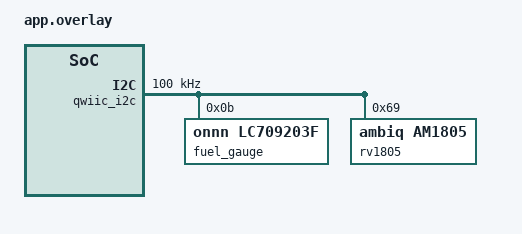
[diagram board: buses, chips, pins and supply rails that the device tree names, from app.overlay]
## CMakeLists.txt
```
# SPDX-License-Identifier: Apache-2.0
#
# ArtemisNano_Hive_Multisense firmware. Adding the app directory to BOARD_ROOT
# makes boards/sparkfun/artemis_nano available as -b sparkfun_artemis_nano.

cmake_minimum_required(VERSION 3.20.0)
list(APPEND BOARD_ROOT ${CMAKE_CURRENT_SOURCE_DIR})
find_package(Zephyr REQUIRED HINTS $ENV{ZEPHYR_BASE})
project(artemis_multisense)

target_sources(app PRIVATE src/main.c src/rv1805.c src/opt4048.c src/bno085.c
  src/person_sensor.c src/hive_ble.c)

# CEVA SH-2 sensor hub library (vendored, unmodified; see lib/sh2/VENDORED.txt).
target_sources(app PRIVATE
  lib/sh2/sh2.c
  lib/sh2/sh2_SensorValue.c
  lib/sh2/sh2_util.c
  lib/sh2/shtp.c
)
target_include_directories(app PRIVATE lib/sh2)
```

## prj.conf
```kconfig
# M4: sensors (RV-1805, LC709203F, OPT4048, BNO085) + BLE MagNET advert and HCP GATT.
CONFIG_GPIO=y
CONFIG_PRINTK=y
CONFIG_I2C=y
CONFIG_RTC=y
CONFIG_FUEL_GAUGE=y
CONFIG_LOG=y
CONFIG_LOG_MODE_IMMEDIATE=y
CONFIG_FPU=y
CONFIG_CBPRINTF_FP_SUPPORT=y
CONFIG_MAIN_STACK_SIZE=2048

# BLE peripheral: MagNET advert + Hanasu HCP GATT service
CONFIG_BT=y
CONFIG_BT_PERIPHERAL=y
CONFIG_BT_MAX_CONN=1
CONFIG_BT_DEVICE_NAME_DYNAMIC=y
CONFIG_BT_DEVICE_NAME_MAX=16
CONFIG_BT_DEVICE_NAME="MagNET"
CONFIG_BT_GATT_DYNAMIC_DB=n
CONFIG_BT_ATT_PREPARE_COUNT=4

# Pairing: Just Works, HCP-AUTH read forces encryption; bonds kept in flash
CONFIG_BT_SMP=y
CONFIG_BT_SMP_ALLOW_UNAUTH_OVERWRITE=y
CONFIG_BT_SETTINGS=y
CONFIG_SETTINGS=y
CONFIG_FLASH=y
CONFIG_FLASH_MAP=y
CONFIG_NVS=y
```

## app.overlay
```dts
/*
 * ArtemisNano_Hive_Multisense app overlay.
 * Qwiic bus (IOM2, SCL pad 27 / SDA pad 25) at 100 kHz with the Multisensor chain:
 *   0x0B LC709203F fuel gauge   (M2, in-tree driver)
 *   0x44 OPT4048 color          (M3, out-of-tree driver)
 *   0x4A BNO085 IMU             (M3, CEVA SH-2 port)
 *   0x69 RV-1805 RTC            (M2, in-tree ambiq,am1805 driver; RV-1805 = AM1805)
 */

/ {
	aliases {
		rtc = &rv1805;
		fuel-gauge0 = &fuel_gauge;
	};
};

&qwiic_i2c {
	clock-frequency = <I2C_BITRATE_STANDARD>;
	status = "okay";

	fuel_gauge: lc709203f@b {
		compatible = "onnn,lc709203f";
		reg = <0x0b>;
		apa = "2000mAh";		/* 3.7 V 2000 mAh LiPo */
		battery-profile = <0x01>;	/* 4.2 V charged (Adafruit default) */
	};

	/* Alarm (CONFIG_RTC_ALARM) needs am1805-gpios = RV-1805 INT -> D6 (pad 43); not wired yet. */
	rv1805: rv1805@69 {
		compatible = "ambiq,am1805";
		reg = <0x69>;
	};
};
```

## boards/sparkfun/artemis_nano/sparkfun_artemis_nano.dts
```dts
/*
 * SPDX-License-Identifier: Apache-2.0
 *
 * SparkFun RedBoard Artemis Nano (DEV-15443), Artemis module = Ambiq Apollo3 Blue.
 * Derived from boards/ambiq/apollo3_evb (Zephyr v4.4.2).
 */

/dts-v1/;
#include <ambiq/ambiq_apollo3_blue.dtsi>

#include "sparkfun_artemis_nano-pinctrl.dtsi"

/ {
	model = "SparkFun RedBoard Artemis Nano";
	compatible = "sparkfun,artemis-nano";

	chosen {
		zephyr,itcm = &tcm;
		zephyr,sram = &sram0;
		zephyr,flash = &flash0;
		zephyr,console = &uart0;
		zephyr,shell-uart = &uart0;
		zephyr,flash-controller = &flash;
		zephyr,code-partition = &slot0_partition;
		zephyr,bt-hci = &bt_hci_apollo;
	};

	aliases {
		watchdog0 = &wdt0;
		led0 = &led0;
	};

	leds {
		compatible = "gpio-leds";

		/* Blue LED D1 on pad 19 via 1k to GND: active high */
		led0: led_0 {
			gpios = <&gpio0_31 19 GPIO_ACTIVE_HIGH>;
			label = "Blue LED";
		};
	};
};

&flash0 {
	erase-block-size = <8192>;
	write-block-size = <4>;

	partitions {
		compatible = "fixed-partitions";
		#address-cells = <1>;
		#size-cells = <1>;

		/* Ambiq secure bootloader: never write */
		internal_boot_partition: partition@0 {
			label = "internal_bootloader";
			reg = <0x00000000 0xc000>;
			read-only;
		};

		/* SparkFun Variable Loader (SVL): USB recovery path, never write */
		svl_partition: partition@c000 {
			label = "svl";
			reg = <0x0000c000 0x4000>;
			read-only;
		};

		/* Application, linked here via CONFIG_FLASH_LOAD_OFFSET=0x10000 */
		slot0_partition: partition@10000 {
			label = "image-0";
			reg = <0x00010000 0xec000>;
		};

		/* 16 KB at the end of the 1 MB flash */
		storage_partition: partition@fc000 {
			label = "storage";
			reg = <0x000fc000 0x4000>;
		};
	};
};

&stimer0 {
	clk-source = <3>;
};

&uart0 {
	current-speed = <115200>;
	pinctrl-0 = <&uart0_default>;
	pinctrl-names = "default";
	status = "okay";
};

&wdt0 {
	status = "okay";
};

/* Qwiic connector, off until a phase needs it */
&iom2 {
	qwiic_i2c: i2c {
		pinctrl-0 = <&i2c2_default>;
		pinctrl-names = "default";
		clock-frequency = <I2C_BITRATE_STANDARD>;
		scl-gpios = <&gpio0_31 27 (GPIO_OPEN_DRAIN | GPIO_PULL_UP)>;
		sda-gpios = <&gpio0_31 25 (GPIO_OPEN_DRAIN | GPIO_PULL_UP)>;
		status = "disabled";
	};
};

/*
 * Servo PWM on D9 (pad 39), timer 2 segment B. Off for phase 2; phase 3 enables it
 * and moves timer 2 to the 3 MHz clock so a 20 ms frame (60000 counts) fits in 16 bits.
 */
&timer2 {
	pwm2: pwm {
		timer-segment = "SEGMENT_B";
		pwm-type = "PWM_REPEAT";
		pinctrl-0 = <&pwm2_default>;
		pinctrl-names = "default";
		status = "disabled";
	};
};

/*
 * BLE: the Apollo3 Blue radio sits inside the Artemis module behind the internal
 * BLEIF, so no pads are needed. The EVB's bleif_default pinmux (pads 30-33, 35, 41)
 * is only applied with CONFIG_SPI_AMBIQ_BLEIF_TIMING_TRACE, so it is left out here
 * and header pins A1/A5/A14/A15 stay free.
 */
&bleif {
	status = "okay";
};

&gpio0_31 {
	status = "okay";
};

&gpio32_63 {
	status = "okay";
};
```

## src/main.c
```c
/*
 * SPDX-License-Identifier: Apache-2.0
 *
 * ArtemisNano_Hive_Multisense.
 *
 * M4: sensors (M2/M3) + BLE.
 *   - RV-1805 RTC (ambiq,am1805 driver + trickle charger), LC709203F fuel gauge,
 *     OPT4048 color (src/opt4048.c), BNO085 IMU via CEVA SH-2 (src/bno085.c).
 *   - Every 10 s: sample everything into one snapshot, print it, refresh the advert.
 *   - BLE (src/hive_ble.c): MagNET advert with the sensor bitmap + readings, and
 *     the Hanasu HCP GATT service answering WHOAMI/STATUS/CAPS/SENSE.
 *
 * Boot check (from P2): blue LED lights before the kernel starts.
 *   LED on, no text -> console pins/baud wrong.  LED off -> image never ran.
 *
 * Blue LED, once running:
 *   1 Hz even blink      -> up, advertising, nobody connected
 *   short pulse / 2.5 s  -> a central is connected
 *   solid on             -> never reached main() (see the boot check above)
 */

#include <stdio.h>
#include <string.h>
#include <zephyr/kernel.h>
#include <zephyr/init.h>
#include <zephyr/sys/byteorder.h>
#include <zephyr/sys/printk.h>
#include <zephyr/drivers/gpio.h>
#include <zephyr/drivers/i2c.h>
#include <zephyr/drivers/rtc.h>
#include <zephyr/drivers/fuel_gauge.h>
#include <cmsis_core.h>
#include <am_mcu_apollo.h>
#include "rv1805.h"
#include "opt4048.h"
#include "bno085.h"
#include "person_sensor.h"
#include "multisense.h"
#include "hive_ble.h"

#define BLUE_LED_PAD 19
#define RV1805_ADDR  0x69
#define OPT4048_ADDR 0x44
#define BNO085_ADDR  0x4A
#define PERSON_ADDR  PERSON_SENSOR_ADDR

/*
 * Full-bus sweep at boot, in addition to the targeted probe of known[].
 *
 * Off by default: it puts a 1-byte read on every one of the ~112 valid 7-bit
 * addresses, including ones no driver owns, and a working node does not need
 * that traffic on every boot. Turn it on when a part that should be present is
 * missing — it is the only way to see a device that moved address (an OPT4048
 * strapped to 0x45 instead of 0x44, say) or one that nobody has added to
 * known[] yet. known[] alone answers "is the Person Sensor there", so the sweep
 * is for the addresses we have not thought of.
 */
#define MS_BUS_SWEEP 0

#define REPORT_PERIOD_MS 10000

/*
 * Blue LED cadence — the only thing this board can say without a console, so
 * the two states must not look alike from across the bench:
 *   advertising, nobody connected : 1 Hz even blink (as it has always been)
 *   a central connected           : a short pulse every 2.5 s
 * The connected pattern is also the cheaper one (80 ms on in 2500 ms, ~3% duty
 * against 50%), which matters for M5: the red power LED is ~1.5 mA and this one
 * is on the same order.
 */
#define LED_ADV_ON_MS    500
#define LED_ADV_OFF_MS   500
#define LED_CONN_ON_MS    80
#define LED_CONN_OFF_MS 2420

/*
 * Last OPT4048 read, kept for the console only (not part of ms_readings, which
 * crosses to hive_ble). M3 printed the error code and the raw channel codes;
 * M4 dropped both, which is why a node whose light sensor stopped reporting
 * could only say "no data" -- no errno, no way to tell darkness from a fault.
 */
static int light_err;
static int presence_err;
static uint32_t light_raw[4];
static uint8_t light_counter;

static const struct gpio_dt_spec led = GPIO_DT_SPEC_GET(DT_ALIAS(led0), gpios);
static const struct device *const qwiic = DEVICE_DT_GET(DT_NODELABEL(qwiic_i2c));
static const struct device *const rtc = DEVICE_DT_GET(DT_ALIAS(rtc));
static const struct device *const gauge = DEVICE_DT_GET(DT_ALIAS(fuel_gauge0));

static const struct {
	uint8_t addr;
	const char *name;
	uint16_t caps;
} known[] = {
	{0x0B, "LC709203F fuel gauge", MS_CAP_BATTERY},
	{0x44, "OPT4048 color", MS_CAP_LUX | MS_CAP_COLOR},
	{0x45, "OPT4048 color (alt)", 0},
	{0x46, "OPT4048 color (alt)", 0},
	{0x4A, "BNO085 IMU", MS_CAP_ORIENTATION},
	{0x4B, "BNO085 IMU (alt)", 0},
	/*
	 * Useful Sensors Person Sensor. v1.0, v1.1 and v2.0 all answer here and are
	 * software-compatible. The M1 scan (2026-10-19) saw an ACK at 0x62 and
	 * recorded it as an unexpected address from a faulty AK9753 board; 0x62 is
	 * this part's documented address, so it was most likely answering correctly.
	 *
	 * src/person_sensor.c reads it, so the capability is claimed here and
	 * cleared again by sensors_bringup() if the probe does not answer.
	 */
	{0x62, "Person Sensor (Useful Sensors)", MS_CAP_PRESENCE},
	{0x69, "RV-1805 RTC", MS_CAP_TIME},
};

static K_MUTEX_DEFINE(snap_lock);
static struct ms_readings snap = {.soc_pct = 0xFF, .tbat_dc = TBAT_NONE_DC};
static uint16_t probed_caps;
static uint8_t device_id[4];

/* Runs before the kernel, drivers and console: drive the LED pad with the HAL. */
static int early_led_on(void)
{
	am_hal_gpio_pinconfig(BLUE_LED_PAD, g_AM_HAL_GPIO_OUTPUT);
	am_hal_gpio_output_set(BLUE_LED_PAD);
	return 0;
}
SYS_INIT(early_led_on, PRE_KERNEL_1, 0);

void ms_readings_get(struct ms_readings *out)
{
	k_mutex_lock(&snap_lock, K_FOREVER);
	*out = snap;
	k_mutex_unlock(&snap_lock);
}

const uint8_t *ms_device_id(void)
{
	return device_id;
}

/* FNV-1a over the two 32-bit chip ID words: stable per part, spreads low-bit differences. */
static void device_id_init(void)
{
	am_hal_mcuctrl_device_t dev;
	uint32_t h = 2166136261u;

	am_hal_mcuctrl_info_get(AM_HAL_MCUCTRL_INFO_DEVICEID, &dev);
	uint32_t words[2] = {dev.ui32ChipID0, dev.ui32ChipID1};

	for (int w = 0; w < 2; w++) {
		for (int b = 0; b < 4; b++) {
			h ^= (words[w] >> (8 * b)) & 0xFF;
			h *= 16777619u;
		}
	}
	sys_put_be32(h, device_id);
	printk("chip id %08x %08x -> node id %02x%02x%02x%02x\n", dev.ui32ChipID0,
	       dev.ui32ChipID1, device_id[0], device_id[1], device_id[2], device_id[3]);
}

/*
 * Probe only the known Multisensor addresses: the I2C driver logs every NACK as an
 * error, so a full 0x08-0x77 sweep floods the console. Answers set the advert's
 * sensor bitmap; a driver that then fails to start clears its bit again.
 */
#if MS_BUS_SWEEP
/* 0x00-0x07 and 0x78-0x7F are reserved by the I2C spec, so they are skipped. */
static void qwiic_sweep(void)
{
	int found = 0;

	printk("qwiic sweep (0x08-0x77):");
	for (uint8_t addr = 0x08; addr <= 0x77; addr++) {
		uint8_t b;

		if (i2c_read(qwiic, &b, 1, addr) != 0) {
			continue;
		}

		const char *name = "not in known[]";

		for (size_t i = 0; i < ARRAY_SIZE(known); i++) {
			if (known[i].addr == addr) {
				name = known[i].name;
				break;
			}
		}
		printk("\n  0x%02x  %s", addr, name);
		found++;
	}
	printk(found ? "\n  %d device(s)\n" : " nothing\n", found);
}
#endif /* MS_BUS_SWEEP */

static void qwiic_scan(void)
{
	int found = 0;

	printk("qwiic probe:");
	for (size_t i = 0; i < ARRAY_SIZE(known); i++) {
		uint8_t b;

		/* A 1-byte read is the probe; all four parts tolerate it. */
		if (i2c_read(qwiic, &b, 1, known[i].addr) == 0) {
			printk("\n  0x%02x  %s", known[i].addr, known[i].name);
			probed_caps |= known[i].caps;
			found++;
		}
	}
	printk(found ? "\n  %d device(s)\n" : " no devices\n", found);
}

/* Build timestamp -> rtc_time, used once when the RTC holds no valid time. */
static void build_time(struct rtc_time *t)
{
	static const char months[] = "JanFebMarAprMayJunJulAugSepOctNovDec";
	char mon[4] = {0};
	int day = 1, year = 2026, h = 0, m = 0, s = 0;
	const char *p;

	sscanf(__DATE__, "%3s %d %d", mon, &day, &year);
	sscanf(__TIME__, "%d:%d:%d", &h, &m, &s);
	p = strstr(months, mon);

	memset(t, 0, sizeof(*t));
	t->tm_year = year - 1900;
	t->tm_mon = p ? (int)((p - months) / 3) : 0;
	t->tm_mday = day;
	t->tm_hour = h;
	t->tm_min = m;
	t->tm_sec = s;
	t->tm_wday = -1;
	t->tm_yday = -1;
	t->tm_isdst = -1;
}

static void rtc_bringup(void)
{
	struct rtc_time now;
	int err;

	err = rv1805_board_init(qwiic, RV1805_ADDR);
	if (err) {
		printk("rv1805: board init failed (%d)\n", err);
	}
	if (!device_is_ready(rtc)) {
		printk("rtc: driver not ready\n");
		probed_caps &= ~MS_CAP_TIME;
		return;
	}

	err = rtc_get_time(rtc, &now);
	if (err || now.tm_year + 1900 < 2026) {
		struct rtc_time t;

		build_time(&t);
		printk("rtc: no valid time (err %d, year %d); setting build time\n", err,
		       err ? 0 : now.tm_year + 1900);
		err = rtc_set_time(rtc, &t);
		if (err) {
			printk("rtc: set failed (%d)\n", err);
		}
	} else {
		printk("rtc: kept time across reset\n");
	}
}

static void sensors_bringup(void)
{
	int err = opt4048_init(qwiic, OPT4048_ADDR);

	if (err) {
		printk("opt4048: init failed (%d)\n", err);
		probed_caps &= ~(MS_CAP_LUX | MS_CAP_COLOR);
	}

	err = bno085_start(qwiic, BNO085_ADDR);
	if (err) {
		printk("bno085: start failed (%d)\n", err);
		probed_caps &= ~MS_CAP_ORIENTATION;
	}
	if (probed_caps & MS_CAP_PRESENCE) {
		err = person_sensor_init(qwiic, PERSON_ADDR);
		if (err) {
			printk("person: init failed (%d)\n", err);
			probed_caps &= ~MS_CAP_PRESENCE;
		}
	}
	if (!device_is_ready(gauge)) {
		probed_caps &= ~MS_CAP_BATTERY;
	}
}

/* Always TBAT_NONE_DC until a thermistor is fitted (then: FUEL_GAUGE_TEMPERATURE
 * with TSENSE enabled in the driver).
 */
static int16_t battery_temp_dc(void)
{
	return TBAT_NONE_DC;
}

/* Read every sensor into a fresh snapshot, then publish it under the lock. */
static void sample(void)
{
	struct ms_readings r = {
		.caps = probed_caps,
		.soc_pct = 0xFF,
		.tbat_dc = battery_temp_dc(),
	};
	struct rtc_time now;

	k_mutex_lock(&snap_lock, K_FOREVER);
	r.seq = snap.seq + 1;
	k_mutex_unlock(&snap_lock);

	if ((r.caps & MS_CAP_TIME) && rtc_get_time(rtc, &now) == 0) {
		/* Field ranges bounded so the compiler can prove the 19-character fit. */
		snprintf(r.time_iso, sizeof(r.time_iso), "%04u-%02u-%02uT%02u:%02u:%02u",
			 (now.tm_year + 1900) % 10000u, (now.tm_mon + 1) % 100u,
			 now.tm_mday % 100u, now.tm_hour % 100u, now.tm_min % 100u,
			 now.tm_sec % 100u);
		r.time_ok = true;
	}

	if (r.caps & MS_CAP_BATTERY) {
		/* No FUEL_GAUGE_TEMPERATURE: with no thermistor the driver fails the whole
		 * request with -ENOTSUP. battery_temp_dc() stands in for it.
		 */
		fuel_gauge_prop_t props[] = {
			FUEL_GAUGE_VOLTAGE,
			FUEL_GAUGE_RELATIVE_STATE_OF_CHARGE,
		};
		union fuel_gauge_prop_val vals[ARRAY_SIZE(props)];

		if (fuel_gauge_get_props(gauge, props, vals, ARRAY_SIZE(props)) == 0) {
			r.vbat_mv = vals[0].voltage / 1000;	/* uV -> mV */
			r.soc_pct = vals[1].relative_state_of_charge;
		}
	}

	if (r.caps & MS_CAP_LUX) {
		struct opt4048_sample s;

		light_err = opt4048_read(qwiic, OPT4048_ADDR, &s);
		if (light_err == 0) {
			r.light_ok = true;
			r.lux = s.lux;
			r.cie_x = s.cie_x;
			r.cie_y = s.cie_y;
			r.cct = s.cct;
			light_raw[0] = s.raw[0];
			light_raw[1] = s.raw[1];
			light_raw[2] = s.raw[2];
			light_raw[3] = s.raw[3];
			light_counter = s.counter;
		}
	}

	if (r.caps & MS_CAP_PRESENCE) {
		struct person_sensor_sample s;

		presence_err = person_sensor_read(qwiic, PERSON_ADDR, &s);
		if (presence_err == 0) {
			const struct person_sensor_face *f = person_sensor_best(&s);

			r.presence_ok = true;
			r.faces = s.num_faces;
			r.best_id = (f && f->id_confidence > 0) ? f->id : -1;
			r.facing = f ? f->is_facing : false;
		}
	}

	if (r.caps & MS_CAP_ORIENTATION) {
		struct bno085_sample s;

		bno085_get(&s);
		if (s.valid) {
			r.imu_ok = true;
			r.yaw = s.yaw;
			r.pitch = s.pitch;
			r.roll = s.roll;
			r.heading_acc_deg = s.accuracy_deg;
			r.stability = s.stability;
			r.sig_motion = s.sig_motion;
		}
	}

	k_mutex_lock(&snap_lock, K_FOREVER);
	snap = r;
	k_mutex_unlock(&snap_lock);
}

static void print_snapshot(void)
{
	struct ms_readings r;

	ms_readings_get(&r);
	printk("#%u time %s", r.seq, r.time_ok ? r.time_iso : "?");
	if (r.caps & MS_CAP_BATTERY) {
		printk("  vbat %u.%03u V  soc %u%%", r.vbat_mv / 1000, r.vbat_mv % 1000, r.soc_pct);
		if (r.tbat_dc == TBAT_NONE_DC) {
			printk("  tbat n/a (no thermistor)");
		} else {
			printk("  tbat %d.%d C", r.tbat_dc / 10, r.tbat_dc % 10);
		}
	}
	printk("\n");

	if (r.light_ok) {
		printk("light  %.1f lux  xy %.4f,%.4f  cct %.0f K  raw %u/%u/%u/%u  cnt %u\n",
		       (double)r.lux, (double)r.cie_x, (double)r.cie_y, (double)r.cct,
		       light_raw[0], light_raw[1], light_raw[2], light_raw[3], light_counter);
	} else if (r.caps & MS_CAP_LUX) {
		/* -EIO bus, -EBADMSG CRC. Detected at boot, so this is not a cable. */
		printk("light  err %d\n", light_err);
	} else {
		printk("light  absent\n");
	}

	if (r.presence_ok) {
		printk("person %u face(s)%s%s\n", r.faces,
		       r.faces && r.facing ? ", facing" : "",
		       r.best_id >= 0 ? ", recognised" : "");
	} else if (r.caps & MS_CAP_PRESENCE) {
		printk("person err %d\n", presence_err);
	} else {
		printk("person absent\n");
	}

	if (r.imu_ok) {
		printk("imu    yaw %.1f pitch %.1f roll %.1f (+/-%.1f deg)  %s  sigmo=%u\n",
		       (double)r.yaw, (double)r.pitch, (double)r.roll, (double)r.heading_acc_deg,
		       bno085_stability_str(r.stability), r.sig_motion);
	} else {
		printk("imu    %s\n", (r.caps & MS_CAP_ORIENTATION) ? "no data yet" : "absent");
	}
}

int main(void)
{
	printk("\n*** artemis_multisense " MS_FW_VERSION " on %s ***\n", CONFIG_BOARD_TARGET);
	printk("VTOR=0x%08x (expect 0x%08x)\n", (unsigned int)SCB->VTOR,
	       (unsigned int)CONFIG_FLASH_LOAD_OFFSET);

	if (!gpio_is_ready_dt(&led) || gpio_pin_configure_dt(&led, GPIO_OUTPUT_ACTIVE) < 0) {
		printk("led0 not ready\n");
		return 0;
	}
	if (!device_is_ready(qwiic)) {
		printk("qwiic_i2c not ready\n");
		return 0;
	}

	device_id_init();
#if MS_BUS_SWEEP
	qwiic_sweep();
#endif
	qwiic_scan();
	rtc_bringup();
	sensors_bringup();
	printk("sensor bitmap 0x%04x\n", probed_caps);

	sample();
	if (hive_ble_start() != 0) {
		printk("ble: not started; sensors only\n");
	}

	/*
	 * Two independent deadlines on one thread: the report period is wall-clock
	 * and must not drift when the LED slows down on connect, and an LED phase
	 * must not stretch because a sample happened to land inside it.
	 */
	int64_t next_sample = k_uptime_get() + REPORT_PERIOD_MS;
	int64_t next_led = k_uptime_get() + LED_ADV_ON_MS;
	bool led_on = true;	/* already on: GPIO_OUTPUT_ACTIVE, and early_led_on() */

	for (;;) {
		const int64_t now = k_uptime_get();

		if (now >= next_sample) {
			sample();
			print_snapshot();
			hive_ble_update();
			next_sample += REPORT_PERIOD_MS;
			continue;
		}

		if (now >= next_led) {
			led_on = !led_on;
			gpio_pin_set_dt(&led, led_on ? 1 : 0);
			/*
			 * The cadence is read at each edge, so a connect or disconnect
			 * shows up within one phase (at worst the 2.4 s off-phase).
			 */
			const bool conn = hive_ble_connected();

			if (led_on) {
				next_led = now + (conn ? LED_CONN_ON_MS : LED_ADV_ON_MS);
			} else {
				next_led = now + (conn ? LED_CONN_OFF_MS : LED_ADV_OFF_MS);
			}
			continue;
		}

		k_msleep((uint32_t)(MIN(next_sample, next_led) - now));
	}
	return 0;
}
```

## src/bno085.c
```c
/* SPDX-License-Identifier: Apache-2.0 */

#include <errno.h>
#include <math.h>
#include <string.h>
#include <zephyr/kernel.h>
#include <zephyr/drivers/i2c.h>
#include <zephyr/sys/printk.h>
#include "sh2.h"
#include "sh2_err.h"
#include "sh2_SensorValue.h"
#include "bno085.h"

#define RV_INTERVAL_US        100000	/* rotation vector, 10 Hz */
#define STABILITY_INTERVAL_US 1000000	/* stability classifier, 1 Hz */
#define SIG_MOTION_ARM_US     1000000	/* any non-zero interval arms the one-shot */
#define POLL_MS               10

static const struct device *bus;
static uint16_t bus_addr;

static struct k_spinlock lock;
static struct bno085_sample latest;
static volatile bool need_config;
static volatile bool need_rearm;
static K_SEM_DEFINE(started, 0, 1);
static int start_err = -ETIMEDOUT;

/* SHTP transfers are at most SH2_HAL_MAX_TRANSFER_IN; the IOM wants word-aligned buffers. */
static uint8_t rx_buf[SH2_HAL_MAX_TRANSFER_IN] __aligned(4);
static uint8_t tx_buf[SH2_HAL_MAX_TRANSFER_OUT] __aligned(4);

/* ---- SH-2 HAL over Zephyr I2C (polled) ---- */

static uint32_t hal_time_us(sh2_Hal_t *self)
{
	ARG_UNUSED(self);
	return (uint32_t)k_ticks_to_us_floor64(k_uptime_ticks());
}

static int hal_open(sh2_Hal_t *self)
{
	/* No RST line yet: SHTP soft reset (channel 1 "executable", command 1). */
	static const uint8_t soft_reset[] = {5, 0, 1, 0, 1};

	ARG_UNUSED(self);
	for (int tries = 0; tries < 5; tries++) {
		memcpy(tx_buf, soft_reset, sizeof(soft_reset));
		if (i2c_write(bus, tx_buf, sizeof(soft_reset), bus_addr) == 0) {
			k_msleep(300);
			return 0;
		}
		k_msleep(30);
	}
	return SH2_ERR_IO;
}

static void hal_close(sh2_Hal_t *self)
{
	ARG_UNUSED(self);
}

/*
 * Every read transaction starts with the 4-byte SHTP header, so read the header
 * to learn the length, then read the whole transfer (header included) again.
 */
static int hal_read(sh2_Hal_t *self, uint8_t *buf, unsigned len, uint32_t *t_us)
{
	uint8_t hdr[4] __aligned(4);
	uint16_t size;

	if (i2c_read(bus, hdr, sizeof(hdr), bus_addr) != 0) {
		return 0;
	}
	size = (hdr[0] | ((uint16_t)hdr[1] << 8)) & 0x7FFF;
	if (size == 0 || size > len || size > sizeof(rx_buf)) {
		return 0;
	}
	if (i2c_read(bus, rx_buf, size, bus_addr) != 0) {
		return 0;
	}
	memcpy(buf, rx_buf, size);
	*t_us = hal_time_us(self);
	return size;
}

static int hal_write(sh2_Hal_t *self, uint8_t *buf, unsigned len)
{
	ARG_UNUSED(self);
	if (len > sizeof(tx_buf)) {
		return 0;
	}
	memcpy(tx_buf, buf, len);
	return i2c_write(bus, tx_buf, len, bus_addr) == 0 ? (int)len : 0;
}

static sh2_Hal_t hal = {
	.open = hal_open,
	.close = hal_close,
	.read = hal_read,
	.write = hal_write,
	.getTimeUs = hal_time_us,
};

/* ---- SH-2 callbacks (run inside sh2_service on the IMU thread) ---- */

static void on_event(void *cookie, sh2_AsyncEvent_t *ev)
{
	ARG_UNUSED(cookie);
	if (ev->eventId == SH2_RESET) {
		k_spinlock_key_t key = k_spin_lock(&lock);

		latest.resets++;
		k_spin_unlock(&lock, key);
		need_config = true;
	}
}

static void on_sensor(void *cookie, sh2_SensorEvent_t *event)
{
	sh2_SensorValue_t v;

	ARG_UNUSED(cookie);
	if (sh2_decodeSensorEvent(&v, event) != SH2_OK) {
		return;
	}

	k_spinlock_key_t key = k_spin_lock(&lock);

	switch (v.sensorId) {
	case SH2_ROTATION_VECTOR: {
		float i = v.un.rotationVector.i, j = v.un.rotationVector.j;
		float k = v.un.rotationVector.k, r = v.un.rotationVector.real;
		const float deg = 57.2957795f;

		latest.qi = i;
		latest.qj = j;
		latest.qk = k;
		latest.qr = r;
		latest.accuracy_deg = v.un.rotationVector.accuracy * deg;
		latest.yaw = atan2f(2.0f * (i * j + k * r), i * i - j * j - k * k + r * r) * deg;
		latest.pitch = asinf(fmaxf(-1.0f, fminf(1.0f, -2.0f * (i * k - j * r)))) * deg;
		latest.roll = atan2f(2.0f * (j * k + i * r), -i * i - j * j + k * k + r * r) * deg;
		latest.reports++;
		latest.valid = true;
		break;
	}
	case SH2_SIGNIFICANT_MOTION:
		latest.sig_motion++;
		need_rearm = true;
		break;
	case SH2_STABILITY_CLASSIFIER:
		latest.stability = v.un.stabilityClassifier.classification;
		break;
	default:
		break;
	}
	k_spin_unlock(&lock, key);
}

static int enable_report(sh2_SensorId_t id, uint32_t interval_us)
{
	sh2_SensorConfig_t cfg = {.reportInterval_us = interval_us};

	return sh2_setSensorConfig(id, &cfg);
}

static void configure(void)
{
	int a = enable_report(SH2_ROTATION_VECTOR, RV_INTERVAL_US);
	int b = enable_report(SH2_STABILITY_CLASSIFIER, STABILITY_INTERVAL_US);
	int c = enable_report(SH2_SIGNIFICANT_MOTION, SIG_MOTION_ARM_US);

	if (a != SH2_OK || b != SH2_OK || c != SH2_OK) {
		printk("bno085: enable reports failed (%d, %d, %d)\n", a, b, c);
		return;
	}
	need_config = false;
	need_rearm = false;
}

static void imu_thread(void *p1, void *p2, void *p3)
{
	sh2_ProductIds_t ids = {0};
	int err;

	ARG_UNUSED(p1);
	ARG_UNUSED(p2);
	ARG_UNUSED(p3);

	err = sh2_open(&hal, on_event, NULL);
	if (err != SH2_OK) {
		start_err = -ENODEV;
		k_sem_give(&started);
		return;
	}
	sh2_setSensorCallback(on_sensor, NULL);

	if (sh2_getProdIds(&ids) == SH2_OK && ids.numEntries > 0) {
		printk("bno085: part %u v%u.%u.%u build %u\n", ids.entry[0].swPartNumber,
		       ids.entry[0].swVersionMajor, ids.entry[0].swVersionMinor,
		       ids.entry[0].swVersionPatch, ids.entry[0].swBuildNumber);
	} else {
		printk("bno085: no product ID response\n");
	}
	configure();
	start_err = 0;
	k_sem_give(&started);

	for (;;) {
		sh2_service();
		if (need_config) {
			printk("bno085: hub reset, re-enabling reports\n");
			configure();
		} else if (need_rearm) {
			/* Significant motion disables itself after firing. */
			need_rearm = false;
			enable_report(SH2_SIGNIFICANT_MOTION, SIG_MOTION_ARM_US);
		}
		k_msleep(POLL_MS);
	}
}

K_THREAD_STACK_DEFINE(imu_stack, 3072);
static struct k_thread imu_tdata;

int bno085_start(const struct device *i2c, uint16_t addr)
{
	bus = i2c;
	bus_addr = addr;
	k_thread_create(&imu_tdata, imu_stack, K_THREAD_STACK_SIZEOF(imu_stack), imu_thread,
			NULL, NULL, NULL, K_PRIO_PREEMPT(8), 0, K_NO_WAIT);
	k_thread_name_set(&imu_tdata, "imu");
	k_sem_take(&started, K_SECONDS(5));
	return start_err;
}

void bno085_get(struct bno085_sample *out)
{
	k_spinlock_key_t key = k_spin_lock(&lock);

	*out = latest;
	k_spin_unlock(&lock, key);
}

const char *bno085_stability_str(uint8_t s)
{
	static const char *const names[] = {"unknown", "on-table", "stationary", "stable",
					    "motion"};

	return s < ARRAY_SIZE(names) ? names[s] : "?";
}
```

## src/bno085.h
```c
/* SPDX-License-Identifier: Apache-2.0 */
#pragma once

#include <stdbool.h>
#include <stdint.h>
#include <zephyr/device.h>

/*
 * BNO085 9-DoF fusion IMU (Adafruit 4754) over I2C, via CEVA's SH-2 library
 * (lib/sh2, Apache-2.0). A dedicated thread owns the SH-2 instance and polls the
 * bus every 10 ms; INT (D8) and RST (D10) are not required yet. Once INT is wired
 * the thread will sleep until it fires instead (M5).
 *
 * Reports enabled: rotation vector (10 Hz), stability classifier (1 Hz) and
 * significant motion (one-shot; re-armed after each event).
 */
struct bno085_sample {
	bool valid;		/* at least one rotation vector received */
	float qi, qj, qk, qr;	/* unit quaternion */
	float accuracy_deg;	/* heading accuracy estimate */
	float yaw, pitch, roll;	/* degrees */
	uint8_t stability;	/* 0 unknown, 1 on table, 2 stationary, 3 stable, 4 motion */
	uint32_t reports;	/* rotation vector reports since boot */
	uint32_t resets;	/* hub resets seen (includes the boot reset) */
	uint32_t sig_motion;	/* significant-motion events since boot */
};

/* Start the IMU thread. Returns 0, or -ENODEV if the hub never answered. */
int bno085_start(const struct device *i2c, uint16_t addr);

/* Copy the latest values. */
void bno085_get(struct bno085_sample *out);

/* Text for bno085_sample.stability. */
const char *bno085_stability_str(uint8_t s);
```

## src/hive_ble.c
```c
/* SPDX-License-Identifier: Apache-2.0 */

#include <stdio.h>
#include <stdarg.h>
#include <string.h>
#include <zephyr/kernel.h>
#include <zephyr/bluetooth/bluetooth.h>
#include <zephyr/bluetooth/conn.h>
#include <zephyr/bluetooth/gatt.h>
#include <zephyr/bluetooth/uuid.h>
#include <zephyr/settings/settings.h>
#include <zephyr/sys/byteorder.h>
#include <zephyr/sys/printk.h>
#include "multisense.h"
#include "hive_ble.h"

#define COMPANY_TEST 0xFFFF
#define ADV_FORMAT   1
#define HDR_LEN      6
#define RSP_LEN      (HDR_LEN + 8)

/* 6d61676e-2d68-6370-0001-0000000000NN: ASCII "magn" "-h" "cp" (Hanasu) */
#define MN_UUID(nn) BT_UUID_128_ENCODE(0x6d61676e, 0x2d68, 0x6370, 0x0001, (nn##ULL))
static const struct bt_uuid_128 svc_uuid = BT_UUID_INIT_128(MN_UUID(0x000000000000));
static const struct bt_uuid_128 cmd_uuid = BT_UUID_INIT_128(MN_UUID(0x000000000001));
static const struct bt_uuid_128 evt_uuid = BT_UUID_INIT_128(MN_UUID(0x000000000002));
static const struct bt_uuid_128 auth_uuid = BT_UUID_INIT_128(MN_UUID(0x000000000003));

static struct bt_conn *cur_conn;
static bool encrypted;
static bool running;
static char name[16];

/* ---- advert payloads ---- */

static uint8_t adv_mfg[2 + HDR_LEN];
static uint8_t rsp_mfg[2 + RSP_LEN];

static const uint8_t adv_flags = BT_LE_AD_GENERAL | BT_LE_AD_NO_BREDR;
static const uint8_t adv_uuid[] = {MN_UUID(0x000000000000)};

static struct bt_data ad[] = {
	BT_DATA(BT_DATA_FLAGS, &adv_flags, 1),
	BT_DATA(BT_DATA_UUID128_ALL, adv_uuid, sizeof(adv_uuid)),
	BT_DATA(BT_DATA_MANUFACTURER_DATA, adv_mfg, sizeof(adv_mfg)),
};
static struct bt_data sd[] = {
	BT_DATA(BT_DATA_NAME_COMPLETE, name, 0),
	BT_DATA(BT_DATA_MANUFACTURER_DATA, rsp_mfg, sizeof(rsp_mfg)),
};

static uint16_t sat_u16(float v)
{
	return v <= 0.0f ? 0 : (v >= 65535.0f ? 65535 : (uint16_t)(v + 0.5f));
}

static void build_payloads(void)
{
	struct ms_readings r;

	ms_readings_get(&r);

	uint8_t *h = &rsp_mfg[2];

	sys_put_le16(COMPANY_TEST, rsp_mfg);
	h[0] = (ADV_FORMAT << 4) | MS_ROLE_MULTISENSOR;
	sys_put_le16(r.caps, &h[1]);
	h[3] = (r.caps & MS_CAP_BATTERY) ? r.soc_pct : 0xFF;
	h[4] = r.seq;
	h[5] = 0;	/* no role bundle installed yet (M7) */

	sys_put_le16(r.light_ok ? sat_u16(r.lux) : 0xFFFF, &h[6]);
	sys_put_le16(r.light_ok ? sat_u16(r.cct) : 0xFFFF, &h[8]);
	sys_put_le16(r.imu_ok ? (uint16_t)(int16_t)r.yaw : 0x8000, &h[10]);
	h[12] = r.imu_ok ? r.stability : 0xFF;
	h[13] = (uint8_t)r.sig_motion;

	memcpy(adv_mfg, rsp_mfg, sizeof(adv_mfg));
}

bool hive_ble_connected(void)
{
	return cur_conn != NULL;
}

static void start_adv(void)
{
	int err;

	build_payloads();
	sd[0].data_len = strlen(name);
	err = bt_le_adv_start(BT_LE_ADV_CONN_FAST_2, ad, ARRAY_SIZE(ad), sd, ARRAY_SIZE(sd));
	if (err && err != -EALREADY) {
		printk("ble: adv start failed (%d)\n", err);
	}
}

void hive_ble_update(void)
{
	if (!running) {
		return;
	}
	build_payloads();
	/* -EAGAIN while connected (not advertising): ignored, refreshed on restart. */
	(void)bt_le_adv_update_data(ad, ARRAY_SIZE(ad), sd, ARRAY_SIZE(sd));
}

/* ---- GATT: Hanasu HCP service ---- */

#define LINE_MAX 200
K_MSGQ_DEFINE(line_q, LINE_MAX, 4, 4);
static char rx_line[LINE_MAX];
static size_t rx_len;

static void post_line(void)
{
	if (rx_len == 0) {
		return;
	}
	rx_line[rx_len] = '\0';
	(void)k_msgq_put(&line_q, rx_line, K_NO_WAIT);	/* never block the BT RX thread */
	rx_len = 0;
}

static void feed(const uint8_t *data, size_t len, bool write_complete)
{
	for (size_t i = 0; i < len; i++) {
		char c = (char)data[i];

		if (c == '\n' || c == '\r') {
			post_line();
			write_complete = false;
		} else if (rx_len < sizeof(rx_line) - 1) {
			rx_line[rx_len++] = c;
		}
	}
	if (write_complete) {
		post_line();
	}
}

static void long_write_flush(struct k_work *w)
{
	ARG_UNUSED(w);
	post_line();
}
static K_WORK_DELAYABLE_DEFINE(long_flush, long_write_flush);

static ssize_t cmd_write(struct bt_conn *conn, const struct bt_gatt_attr *attr, const void *buf,
			 uint16_t len, uint16_t offset, uint8_t flags)
{
	ARG_UNUSED(attr);
	if (flags & BT_GATT_WRITE_FLAG_PREPARE) {
		return 0;
	}
	if (flags & BT_GATT_WRITE_FLAG_EXECUTE) {
		if (offset == 0) {
			rx_len = 0;
		}
		feed(buf, len, false);
		k_work_reschedule(&long_flush, K_MSEC(20));
		return len;
	}
	/* A write of exactly (MTU-3) may continue; anything else ends the line. */
	feed(buf, len, len != bt_gatt_get_mtu(conn) - 3);
	return len;
}

static ssize_t auth_read(struct bt_conn *conn, const struct bt_gatt_attr *attr, void *buf,
			 uint16_t len, uint16_t offset)
{
	static const char ok[] = "bonded";

	return bt_gatt_attr_read(conn, attr, buf, len, offset, ok, sizeof(ok) - 1);
}

static ssize_t evt_read(struct bt_conn *conn, const struct bt_gatt_attr *attr, void *buf,
			uint16_t len, uint16_t offset)
{
	return bt_gatt_attr_read(conn, attr, buf, len, offset, "", 0);
}

static void evt_ccc_changed(const struct bt_gatt_attr *attr, uint16_t value)
{
	ARG_UNUSED(attr);
	ARG_UNUSED(value);
}

BT_GATT_SERVICE_DEFINE(hcp_svc,
	BT_GATT_PRIMARY_SERVICE(&svc_uuid),
	BT_GATT_CHARACTERISTIC(&cmd_uuid.uuid, BT_GATT_CHRC_WRITE | BT_GATT_CHRC_WRITE_WITHOUT_RESP,
			       BT_GATT_PERM_WRITE | BT_GATT_PERM_PREPARE_WRITE, NULL, cmd_write,
			       NULL),
	BT_GATT_CHARACTERISTIC(&evt_uuid.uuid, BT_GATT_CHRC_NOTIFY | BT_GATT_CHRC_READ,
			       BT_GATT_PERM_READ, evt_read, NULL, NULL),
	BT_GATT_CCC(evt_ccc_changed, BT_GATT_PERM_READ | BT_GATT_PERM_WRITE),
	BT_GATT_CHARACTERISTIC(&auth_uuid.uuid, BT_GATT_CHRC_READ, BT_GATT_PERM_READ_ENCRYPT,
			       auth_read, NULL, NULL),
);
#define EVT_ATTR (&hcp_svc.attrs[4])

/* Chunk to (MTU-3); the client reassembles at '\n'. Also echoed to the console. */
static void write_line(const char *line)
{
	struct bt_conn *conn = cur_conn;
	char buf[256];

	printk("hcp> %s\n", line);
	if (!conn || !bt_gatt_is_subscribed(conn, EVT_ATTR, BT_GATT_CCC_NOTIFY)) {
		return;
	}

	size_t chunk = MIN(bt_gatt_get_mtu(conn) - 3, sizeof(buf) - 1);
	size_t len = strlen(line);

	for (size_t off = 0; off <= len; off += chunk) {
		size_t n = len - off;
		/* Strictly less: the '\n' must fit in the same notification. A line of
		 * exactly `chunk` bytes goes out full, then the '\n' alone next pass.
		 */
		bool last = n < chunk;
		int rc = -ENOMEM;

		if (!last) {
			n = chunk;
		}
		memcpy(buf, line + off, n);
		if (last) {
			buf[n++] = '\n';
		}
		for (int attempt = 0; attempt < 12 && rc != 0; attempt++) {
			rc = bt_gatt_notify(conn, EVT_ATTR, buf, n);
			if (rc == -ENOMEM || rc == -ENOBUFS) {
				k_msleep(10);
			} else if (rc != 0) {
				printk("ble: notify failed (%d) at %u/%u\n", rc, off, len);
				return;
			}
		}
		if (rc != 0 || last) {
			return;
		}
	}
}

/* ---- minimal HCP dispatcher (until the shared core arrives in M7) ---- */

static void respond(const char *tag, const char *body)
{
	char out[320];

	if (tag[0]) {
		snprintf(out, sizeof(out), "@%s %s", tag, body);
	} else {
		snprintf(out, sizeof(out), "%s", body);
	}
	write_line(out);
}

static const char *stability_str(uint8_t s)
{
	static const char *const names[] = {"unknown", "on-table", "stationary", "stable",
					    "motion"};

	return s < ARRAY_SIZE(names) ? names[s] : "?";
}

/*
 * Append to a line, saturating at the end of the buffer.
 *
 * The plain `n = append(buf, cap, n, ...)` idiom is fine until `n`
 * reaches `cap`: then `cap - n` is a *negative value converted to size_t*,
 * snprintf is told the buffer is gigantic, and it writes off the end. snprintf
 * also returns the length it *would* have written, so `n` can exceed `cap`
 * after a clean truncation and the next call is the one that overruns. Both
 * lines below are within budget today (CAPS 251, SENSE 210 of 320 worst case),
 * but the margin is one new sensor wide, so the idiom goes away.
 */
static int append(char *buf, size_t cap, int n, const char *fmt, ...)
{
	va_list ap;
	int w;

	if (n < 0 || (size_t)n >= cap) {
		return (int)cap;
	}
	va_start(ap, fmt);
	w = vsnprintf(buf + n, cap - n, fmt, ap);
	va_end(ap);
	if (w < 0) {
		return (int)cap;
	}
	n += w;
	return (size_t)n > cap ? (int)cap : n;
}

static void sense_line(char *buf, size_t cap)
{
	struct ms_readings r;
	int n;

	ms_readings_get(&r);
	n = snprintf(buf, cap, "+OK seq=%u", r.seq);
	if (r.time_ok) {
		n = append(buf, cap, n, " time=%s", r.time_iso);
	}
	if (r.caps & MS_CAP_BATTERY) {
		n = append(buf, cap, n, " vbat=%u.%03u soc=%u", r.vbat_mv / 1000,
			      r.vbat_mv % 1000, r.soc_pct);
		n = append(buf, cap, n, r.tbat_dc == TBAT_NONE_DC ? " tbat=na" : " tbat=%d.%d",
			      r.tbat_dc / 10, r.tbat_dc % 10);
	}
	if (r.presence_ok) {
		n = append(buf, cap, n, " faces=%u facing=%u", r.faces, r.facing ? 1 : 0);
		if (r.best_id >= 0) {
			n = append(buf, cap, n, " faceid=%d", r.best_id);
		}
	}
	if (r.light_ok) {
		n = append(buf, cap, n, " lux=%.1f cct=%.0f x=%.4f y=%.4f", (double)r.lux,
			      (double)r.cct, (double)r.cie_x, (double)r.cie_y);
	}
	if (r.imu_ok) {
		n = append(buf, cap, n, " yaw=%.1f pitch=%.1f roll=%.1f hacc=%.0f motion=%s sigmo=%u",
			   (double)r.yaw, (double)r.pitch, (double)r.roll, (double)r.heading_acc_deg,
			   stability_str(r.stability), r.sig_motion);
	}
}

static void caps_line(char *buf, size_t cap)
{
	struct ms_readings r;
	int n;

	ms_readings_get(&r);
	n = snprintf(buf, cap,
		     "+OK proto=2.1 fw=" MS_FW_VERSION " maxline=%d transports=ble "
		     "verbs=PING,HELP,WHOAMI,STATUS,CAPS,SENSE,CHANNEL,ADMIN mode=HCP role=multisensor sensors=",
		     LINE_MAX);
	const char *sep = "";

	if (r.caps & MS_CAP_PRESENCE) {
		n = append(buf, cap, n, "%spresence:person_sensor", sep);
		sep = ",";
	}
	if (r.caps & MS_CAP_ORIENTATION) {
		n = append(buf, cap, n, "%sorientation:bno085,motion:bno085", sep);
		sep = ",";
	}
	if (r.caps & MS_CAP_LUX) {
		n = append(buf, cap, n, "%slux:opt4048,cct:opt4048", sep);
		sep = ",";
	}
	if (r.caps & MS_CAP_TIME) {
		n = append(buf, cap, n, "%stime:rv1805", sep);
		sep = ",";
	}
	if (r.caps & MS_CAP_BATTERY) {
		n = append(buf, cap, n, "%sbattery:lc709203f", sep);
	}
}

static void dispatch(char *line)
{
	char tag[16] = "";
	char body[320];
	const uint8_t *id = ms_device_id();
	char *p = line;

	while (*p == ' ') {
		p++;
	}
	if (*p == '@') {
		size_t i = 0;

		p++;
		while (*p && *p != ' ' && i < sizeof(tag) - 1) {
			tag[i++] = *p++;
		}
		tag[i] = '\0';
		while (*p == ' ') {
			p++;
		}
	}
	char *verb = p;

	while (*p && *p != ' ') {
		p++;
	}
	char *rest = p;

	if (*rest == ' ') {
		*rest++ = '\0';
		while (*rest == ' ') {
			rest++;
		}
	}

	if (verb[0] == '\0') {
		respond(tag, "-ERR E_SYNTAX empty");
	} else if (!strcmp(verb, "PING")) {
		respond(tag, "+PONG");
	} else if (!strcmp(verb, "HELP")) {
		write_line("# HCP verbs: PING HELP WHOAMI STATUS CAPS SENSE  CHANNEL SHOW  ADMIN LIST");
		respond(tag, "+OK");
	} else if (!strcmp(verb, "WHOAMI")) {
		snprintf(body, sizeof(body), "+OK id=%02x%02x%02x%02x name=%s fw=" MS_FW_VERSION,
			 id[0], id[1], id[2], id[3], name);
		respond(tag, body);
	} else if (!strcmp(verb, "STATUS")) {
		snprintf(body, sizeof(body),
			 "+OK state=READY role=multisensor channel=none peers=0 name=%s "
			 "id=%02x%02x%02x%02x ble=up link=%s",
			 name, id[0], id[1], id[2], id[3], encrypted ? "encrypted" : "open");
		respond(tag, body);
	} else if (!strcmp(verb, "CAPS")) {
		caps_line(body, sizeof(body));
		respond(tag, body);
	} else if (!strcmp(verb, "SENSE")) {
		sense_line(body, sizeof(body));
		respond(tag, body);
	} else if (!strcmp(verb, "CHANNEL")) {
		/* No mesh channel on this node yet (BLE-only until M7). magnet_app's node
		 * screen reads CHANNEL SHOW on every refresh, so answer it honestly.
		 */
		if (!strncmp(rest, "SHOW", 4) || !strncmp(rest, "LIST", 4)) {
			respond(tag, "+OK name=none selector=- path=-");
		} else {
			respond(tag, "-ERR E_UNSUPPORTED no mesh channel on this node yet");
		}
	} else if (!strcmp(verb, "ADMIN")) {
		/* Empty allow-list: no privileged verbs exist here yet. */
		if (!strncmp(rest, "LIST", 4)) {
			respond(tag, "+OK");
		} else {
			respond(tag, "-ERR E_UNSUPPORTED no privileged verbs on this node yet");
		}
	} else {
		snprintf(body, sizeof(body), "-ERR E_UNKNOWN %s", verb);
		respond(tag, body);
	}
}

static void hcp_thread(void *p1, void *p2, void *p3)
{
	char line[LINE_MAX];

	ARG_UNUSED(p1);
	ARG_UNUSED(p2);
	ARG_UNUSED(p3);
	for (;;) {
		k_msgq_get(&line_q, line, K_FOREVER);
		printk("hcp< %s\n", line);
		dispatch(line);
	}
}
K_THREAD_DEFINE(hcp_tid, 2048, hcp_thread, NULL, NULL, NULL, K_PRIO_PREEMPT(9), 0, 0);

/* ---- connection + security ---- */

static void connected(struct bt_conn *conn, uint8_t err)
{
	char addr[BT_ADDR_LE_STR_LEN];

	if (err) {
		printk("ble: connect failed (0x%02x)\n", err);
		return;
	}
	bt_addr_le_to_str(bt_conn_get_dst(conn), addr, sizeof(addr));
	printk("ble: connected %s\n", addr);
	cur_conn = bt_conn_ref(conn);
	encrypted = false;
	/* No Security Request here (unlike Hanasu): Windows turns it into a pairing
	 * prompt that blocks the first write, and every verb so far is read-only.
	 * A host that wants an encrypted link reads HCP-AUTH, which forces pairing.
	 */
}

static void disconnected(struct bt_conn *conn, uint8_t reason)
{
	if (conn != cur_conn) {
		return;
	}
	printk("ble: disconnected (reason 0x%02x)\n", reason);
	bt_conn_unref(cur_conn);
	cur_conn = NULL;
	encrypted = false;
}

/* Restart advertising only once the connection object is free again. */
static void recycled(void)
{
	if (running) {
		start_adv();
	}
}

static void security_changed(struct bt_conn *conn, bt_security_t level, enum bt_security_err err)
{
	ARG_UNUSED(conn);
	encrypted = (err == BT_SECURITY_ERR_SUCCESS) && level >= BT_SECURITY_L2;
	printk("ble: link %s (level %d err %d)\n", encrypted ? "encrypted" : "NOT encrypted",
	       level, err);
}

BT_CONN_CB_DEFINE(conn_cb) = {
	.connected = connected,
	.disconnected = disconnected,
	.recycled = recycled,
	.security_changed = security_changed,
};

/* Screenless node: accept numeric comparison (Just Works in effect). */
static void passkey_confirm(struct bt_conn *conn, unsigned int passkey)
{
	ARG_UNUSED(passkey);
	bt_conn_auth_passkey_confirm(conn);
}

static void pairing_cancel(struct bt_conn *conn)
{
	ARG_UNUSED(conn);
}

static struct bt_conn_auth_cb auth_cb = {
	.passkey_confirm = passkey_confirm,
	.cancel = pairing_cancel,
};

static void mtu_updated(struct bt_conn *conn, uint16_t tx, uint16_t rx)
{
	ARG_UNUSED(conn);
	printk("ble: mtu tx=%u rx=%u\n", tx, rx);
}

static struct bt_gatt_cb gatt_cb = {.att_mtu_updated = mtu_updated};

int hive_ble_start(void)
{
	const uint8_t *id = ms_device_id();
	bt_addr_le_t addrs[1];
	size_t count = 1;
	char addr[BT_ADDR_LE_STR_LEN];
	int err;

	bt_conn_auth_cb_register(&auth_cb);
	bt_gatt_cb_register(&gatt_cb);

	err = bt_enable(NULL);
	if (err) {
		printk("ble: bt_enable failed (%d)\n", err);
		return err;
	}
	settings_load_subtree("bt");

	snprintf(name, sizeof(name), "MagNET-%02x%02x", id[2], id[3]);
	bt_set_name(name);

	bt_id_get(addrs, &count);
	if (count) {
		bt_addr_le_to_str(&addrs[0], addr, sizeof(addr));
		printk("ble: %s advertising as %s\n", name, addr);
	}

	running = true;
	start_adv();
	return 0;
}
```

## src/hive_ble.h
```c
/* SPDX-License-Identifier: Apache-2.0 */
#pragma once

#include <stdbool.h>

/*
 * MagNET BLE for the Multisensor (M4).
 *
 * Advert (README 5.1): flags + HCP service UUID (as Hanasu) + manufacturer data,
 * company 0xFFFF (testing), 6-byte header:
 *   [0] version<<4 | role (0x1F)  [1..2] sensor bitmap LE  [3] battery %
 *   [4] sequence  [5] bundle tag
 * Scan response: "MagNET-xxxx" + manufacturer data = the same header + readings:
 *   [6..7] lux (u16 LE, saturating)  [8..9] CCT K (u16 LE)  [10..11] yaw deg (s16 LE)
 *   [12] stability  [13] significant-motion count (low byte)
 * (Android merges advert + scan response per company ID, so the scan response
 * repeats the header rather than carrying readings alone.)
 *
 * GATT: the Hanasu HCP service (…0000) with CMD (…0001), EVT (…0002, notify),
 * AUTH (…0003, read-encrypted). A small built-in dispatcher answers PING, HELP,
 * WHOAMI, STATUS, CAPS, SENSE, CHANNEL SHOW (none yet) and ADMIN LIST (empty)
 * until the full HCP core lands (M7). magnet_app's node screen needs the last two.
 */

/* Bring up the controller, load bonds, start advertising. */
int hive_ble_start(void);

/* Refresh advert + scan response from the latest snapshot. */
void hive_ble_update(void);

/*
 * True while a central is connected. Used by main() to slow the blue LED to a
 * heartbeat, so the board says which state it is in without a console.
 */
bool hive_ble_connected(void);
```

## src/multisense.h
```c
/* SPDX-License-Identifier: Apache-2.0 */
#pragma once

#include <stdbool.h>
#include <stdint.h>
#include <zephyr/sys/util.h>

/*
 * Shared state between the sensor loop (main.c) and the radio (hive_ble.c).
 * main.c owns the sensors and publishes a snapshot every report period.
 */

/* Advert sensor bitmap (README 5.1). Set from the boot probe, never hard-coded. */
#define MS_CAP_PRESENCE    BIT(0)
#define MS_CAP_LUX         BIT(1)
#define MS_CAP_COLOR       BIT(2)
#define MS_CAP_TIME        BIT(3)
#define MS_CAP_BATTERY     BIT(4)
#define MS_CAP_SOUND       BIT(5)
#define MS_CAP_ORIENTATION BIT(6)

#define MS_ROLE_MULTISENSOR 15
#define MS_FW_VERSION       "0.5.0-m4"

/* Battery temperature sentinel until a thermistor is fitted (deci-degrees C). */
#define TBAT_NONE_DC INT16_MIN

struct ms_readings {
	uint16_t caps;		/* MS_CAP_* detected at boot */
	uint8_t seq;		/* increments with each snapshot */

	/* battery (MS_CAP_BATTERY) */
	uint16_t vbat_mv;
	uint8_t soc_pct;	/* 0xFF = unknown */
	int16_t tbat_dc;	/* TBAT_NONE_DC = no thermistor */

	/* light (MS_CAP_LUX / MS_CAP_COLOR) */
	bool light_ok;
	float lux;
	float cie_x, cie_y;
	float cct;

	/* IMU (MS_CAP_ORIENTATION) */
	bool imu_ok;
	float yaw, pitch, roll;
	float heading_acc_deg;
	uint8_t stability;	/* 0 unknown, 1 on table, 2 stationary, 3 stable, 4 motion */
	uint32_t sig_motion;

	/* presence (MS_CAP_PRESENCE) -- Person Sensor at 0x62 */
	bool presence_ok;
	uint8_t faces;		/* 0-4 in frame */
	int8_t best_id;		/* recognised ID 0-7, or -1 */
	bool facing;		/* the best face is looking at the sensor */

	/* time (MS_CAP_TIME) */
	bool time_ok;
	char time_iso[32];	/* YYYY-MM-DDTHH:MM:SS (sized for the compiler's worst case) */
};

/* Copy the latest snapshot (thread-safe). */
void ms_readings_get(struct ms_readings *out);

/* Stable 4-byte node ID from the Apollo3 chip ID. */
const uint8_t *ms_device_id(void);
```

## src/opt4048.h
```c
/* SPDX-License-Identifier: Apache-2.0 */
#pragma once

#include <stdint.h>
#include <zephyr/device.h>

/*
 * TI OPT4048 tristimulus color sensor (Adafruit 6335). Zephyr has no driver, so
 * this is a small register-level one: continuous auto-range conversions, burst
 * read of all four channels with CRC check, CIE 1931 xy + lux + CCT from the
 * datasheet matrix (same coefficients as Adafruit_OPT4048).
 */
struct opt4048_sample {
	uint32_t raw[4];	/* ADC codes CH0..CH3 (X, Y, Z, W) */
	uint8_t counter;	/* CH0 conversion counter, 0-15, wraps; increments per conversion */
	float lux;
	float cie_x;
	float cie_y;
	float cct;		/* Kelvin, 0 when the light is too dim to compute */
};

/* Returns 0, -ENODEV (no answer), -ENOTSUP (wrong device ID) or -EIO. */
int opt4048_init(const struct device *i2c, uint16_t addr);

/*
 * Returns 0, -EBADMSG (CRC mismatch) or -EIO.
 *
 * **Zero is a valid reading.** A covered or unlit sensor really does report
 * zero on all four channels, so this no longer reports that as -EAGAIN: doing
 * so made darkness indistinguishable from a broken part, and the node then
 * published "no light sensor data" instead of "0 lux". opt4048_init() waits out
 * the first conversion so a read is always against converted data.
 */
int opt4048_read(const struct device *i2c, uint16_t addr, struct opt4048_sample *s);
```

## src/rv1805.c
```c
/* SPDX-License-Identifier: Apache-2.0 */

#include <errno.h>
#include <zephyr/drivers/i2c.h>
#include <zephyr/sys/printk.h>
#include "rv1805.h"

#define REG_TRICKLE   0x20
#define REG_CONF_KEY  0x1F
#define REG_CAP_RC    0x26
#define REG_ID0       0x28

#define PART_ID0      0x18	/* AM1805 / RV-1805 part number, upper byte */
#define CONF_KEY_WRT  0x9D	/* unlocks trickle, BREF, CAPRC, batmode, output control */
#define CAP_RC_ENABLE 0xA0	/* enable the CAP_RC pin (supercap) */
#define TRICKLE_ON    0xA5	/* TCS=1010 (enable), diode 0.3 V, ROUT 3 kOhm */

int rv1805_board_init(const struct device *i2c, uint16_t addr)
{
	uint8_t id[2];
	uint8_t trickle;

	if (i2c_burst_read(i2c, addr, REG_ID0, id, sizeof(id)) != 0) {
		return -ENODEV;
	}
	printk("rv1805: ID0=0x%02x ID1=0x%02x\n", id[0], id[1]);
	if (id[0] != PART_ID0) {
		return -ENOTSUP;
	}

	/* CONF_KEY re-locks after each protected write, so unlock before each. */
	if (i2c_reg_write_byte(i2c, addr, REG_CONF_KEY, CONF_KEY_WRT) ||
	    i2c_reg_write_byte(i2c, addr, REG_CAP_RC, CAP_RC_ENABLE) ||
	    i2c_reg_write_byte(i2c, addr, REG_CONF_KEY, CONF_KEY_WRT) ||
	    i2c_reg_write_byte(i2c, addr, REG_TRICKLE, TRICKLE_ON)) {
		return -EIO;
	}

	if (i2c_reg_read_byte(i2c, addr, REG_TRICKLE, &trickle) == 0) {
		printk("rv1805: trickle=0x%02x (expect 0x%02x)\n", trickle, TRICKLE_ON);
	}
	return 0;
}
```

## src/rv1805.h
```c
/* SPDX-License-Identifier: Apache-2.0 */
#pragma once

#include <zephyr/device.h>

/*
 * RV-1805 setup the upstream ambiq,am1805 driver does not do: verify the part
 * number and enable the supercap trickle charger (otherwise the backup cap never
 * charges and time is lost on power-off). Values from SparkFun_RV-1805 begin().
 * Returns 0, -ENODEV (no answer), -ENOTSUP (wrong part) or -EIO.
 */
int rv1805_board_init(const struct device *i2c, uint16_t addr);
```
